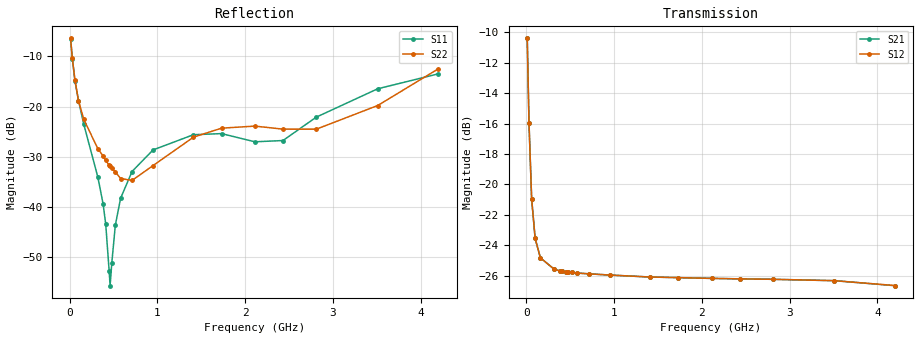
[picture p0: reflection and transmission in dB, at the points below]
! Integrated Device Technology
! Corporate Headquarters
! 6024 Silver Creek Valley Road
! San Jose, CA 95138  USA
! Phone:  1-408-284-8200
! Toll Free:  1-800-223-1366
! Webpage:  http://www.idt.com/
! Timing and RF Division
! 515 Groton Road, Suite 102
! Westford, MA 01886-6024
! Device:  F1950
! Description: 7-bit 0.25 dB Digital Step Attenuator
! Frequency:  150.0 -  4000.00 MHz
! Package:  4x4 mm Thin QFN Plastic Package: 24 pin
! Ports:  2 RF, 12 DC
!  Pin  1  = D0
!  Pin  2  = VDD
!  Pin  3  = Vmode
!  Pin  4  = GND
!  Pin  5  = RF1  =  Port 1
!  Pin  6  = GND
!  Pin  7  = GND
!  Pin  8  = GND
!  Pin  9  = GND
!  Pin 10  = GND
!  Pin 11  = GND
!  Pin 12  = GND
!  Pin 13  = GND
!  Pin 14  = RF2  =  Port 2
!  Pin 15  = GND
!  Pin 16  = LE
!  Pin 17  = CLK
!  Pin 18  = DATE
!  Pin 19  = D6
!  Pin 20  = D5
!  Pin 21  = D4
!  Pin 22  = D3
!  Pin 23  = D2
!  Pin 24  = D1
! State:  100
! Atten State:  25.00 dB
! Voltage:  +5.00 Volts
! Current:  Not Measured mA
! Data:  The device was measured on a the F195X evaluation board which has
!  individual transmission lines to the RF pins.  Data was collected
!  using a calibrated network analyzer.  The evaluation board was
!  de-embedded using a TRL calibration technique.
!  The reference plane is the edge of the package pin.
! Misc:  Board 2019
!  Action Tracker AT0250
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# GHz S dB R 50
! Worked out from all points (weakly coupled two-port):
!   420 points, 10 MHz to 4.2 GHz, reference 50 ohm
!   highest |S21| = -10.39 dB at 10 MHz (marker M1); lowest = -26.7 dB at 4.2 GHz (marker M2)
!   lowest |S11| = -55.6 dB at 460 MHz (marker M3), VSWR 1.00, Z = 49.9 - j0.1 ohm
!   |S11| at or under -10 dB: 27.69 MHz to end of sweep
!   |S22| runs from -34.9 to -6.4 dB; largest |S21 - S12| = 0.00011
!   S11 on the Smith chart (normalised r, x): 10 MHz: 2.07, -1.12; 30 MHz: 1.29, -0.65; 60 MHz: 1.11, -0.37; 380 MHz: 1.01, -0.02; 4.2 GHz: 0.68, +0.17
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0.01  -6.47 -26.2  -10.39 -32.6  -10.39 -32.6  -6.40 -27.2
0.03  -10.44 -50.5  -15.96 -52.5  -15.96 -52.5  -10.37 -51.9
0.06  -14.91 -63.7  -20.94 -48.8  -20.94 -48.8  -14.69 -65.2
0.1  -18.79 -70.4  -23.55 -37.5  -23.55 -37.5  -18.77 -70.7
0.16  -23.47 -72.3  -24.83 -27.1  -24.83 -27.1  -22.50 -75.8
0.32  -33.95 -71.6  -25.59 -17.2  -25.59 -17.2  -28.33 -83.7
0.38  -39.29 -70.9  -25.68 -15.9  -25.68 -15.9  -29.80 -86.3
0.41  -43.28 -77.2  -25.71 -15.5  -25.71 -15.5  -30.67 -87.9
0.45  -52.76 -109.1  -25.75 -15.0  -25.75 -15.0  -31.69 -93.5
0.46  -55.61 -142.6  -25.76 -14.9  -25.75 -15.0  -31.88 -95.1
0.48  -51.05 157.0  -25.77 -14.8  -25.77 -14.8  -32.18 -97.9
0.52  -43.56 141.2  -25.79 -14.5  -25.79 -14.6  -32.97 -101.5
0.58  -38.22 135.6  -25.83 -14.4  -25.83 -14.4  -34.29 -113.5
0.71  -32.90 138.3  -25.88 -14.6  -25.88 -14.6  -34.67 -138.5
0.95  -28.59 146.5  -25.96 -15.7  -25.96 -15.7  -31.71 -175.5
1.41  -25.57 163.1  -26.09 -19.0  -26.09 -19.0  -26.06 161.2
1.73  -25.35 168.4  -26.13 -21.6  -26.13 -21.6  -24.27 152.7
2.11  -26.98 158.0  -26.18 -25.3  -26.18 -25.3  -23.86 142.9
2.43  -26.73 126.6  -26.21 -28.0  -26.21 -28.1  -24.46 132.3
2.81  -22.07 105.5  -26.24 -31.9  -26.24 -31.9  -24.47 117.0
3.51  -16.43 117.5  -26.33 -38.6  -26.33 -38.7  -19.76 113.9
4.2  -13.46 145.6  -26.66 -43.1  -26.65 -43.1  -12.46 127.5
